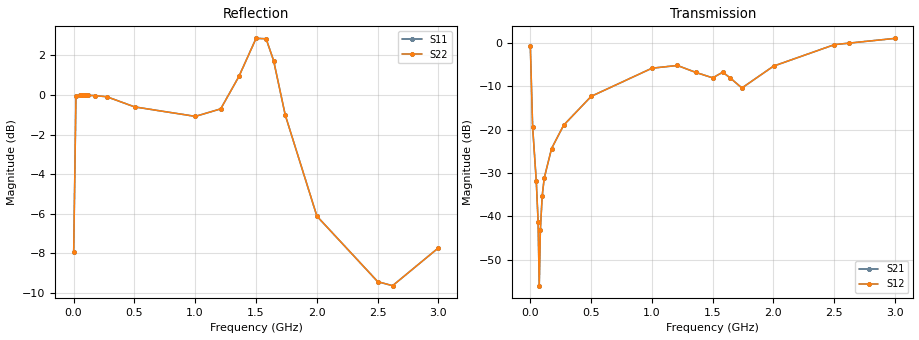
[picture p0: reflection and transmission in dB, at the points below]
!s-Parameter Generated by FASTRON Sdn. Bhd.
!FASTRON P/N : MICC-6R8X
!Keysight Technologies,E4991B,MY54100416,A.01.15
!Date: Fri Aug 28 10:54:06 2026
!Version  : Rev00 Fri Aug 28 10:54:06 2026
!Data & Calibration Information:
!PortZ  Port1:50+j0  Port2:50+j0
!When reading, reference impedance value at option line is always used.
!Remarks : This data is being provided solely for informational purposes.
!Freq	S11	S21	S12	S22
# Hz S dB R 50
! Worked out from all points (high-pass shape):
!   1601 points, 1 MHz to 3 GHz, reference 50 ohm
!   highest |S21| = 0.98 dB at 3 GHz (marker M1); lowest = -55.9 dB at 74.1 MHz (marker M2)
!   |S21| within 3 dB of the highest: start of sweep to 1.64 MHz; 2.26 GHz to end of sweep
!   lowest |S11| = -9.6 dB at 2.623 GHz (marker M3), VSWR 1.98, Z = 45.7 - j33.1 ohm
!   |S11| at or under -10 dB: nowhere
!   |S22| runs from -9.6 to 3.1 dB; largest |S21 - S12| = 0
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1000000  -7.95 64.8  -0.87 -23.6  -0.87 -23.6  -7.95 64.8
1.974375e7  -0.07 6.2  -19.38 -82.8  -19.38 -82.8  -0.07 6.2
4.973375e7  -0.01 1.5  -31.87 -85.8  -31.87 -85.8  -0.01 1.5
6.472875e7  -0.01 0.5  -41.17 -79.9  -41.17 -79.9  -0.01 0.5
7.410062e7  -0.01 0.0  -55.94 -16.1  -55.94 -16.1  -0.01 0.0
8.34725e7  -0.01 -0.4  -43.06 77.1  -43.06 77.1  -0.01 -0.4
9.84675e7  -0.01 -1.0  -35.23 84.0  -35.23 84.0  -0.01 -1.0
1.153369e8  -0.02 -1.6  -31.14 85.3  -31.14 85.3  -0.02 -1.6
1.753169e8  -0.03 -3.5  -24.38 84.9  -24.38 84.9  -0.03 -3.5
2.746588e8  -0.09 -6.4  -19.01 81.7  -19.01 81.7  -0.09 -6.4
5.014581e8  -0.60 -13.8  -12.36 67.2  -12.36 67.2  -0.60 -13.8
1.001916e9  -1.08 -30.5  -5.88 62.0  -5.88 62.0  -1.08 -30.5
1.209972e9  -0.70 -32.7  -5.26 65.8  -5.26 65.8  -0.70 -32.7
1.359922e9  0.94 -24.1  -6.84 92.1  -6.84 92.1  0.94 -24.1
1.5005e9  2.86 -2.6  -8.11 170.9  -8.11 170.9  2.86 -2.6
1.582972e9  2.84 11.9  -6.80 -141.2  -6.80 -141.2  2.84 11.9
1.644827e9  1.74 16.8  -8.14 -115.6  -8.14 -115.6  1.74 16.8
1.74042e9  -1.01 17.1  -10.44 -60.4  -10.44 -60.4  -1.01 17.1
2.000958e9  -6.12 -14.7  -5.40 13.5  -5.40 13.5  -6.12 -14.7
2.501416e9  -9.43 -71.4  -0.46 19.7  -0.46 19.7  -9.43 -71.4
2.623251e9  -9.63 -78.3  -0.11 19.1  -0.11 19.1  -9.63 -78.3
3e9  -7.72 -95.9  0.98 21.4  0.98 21.4  -7.72 -95.9
